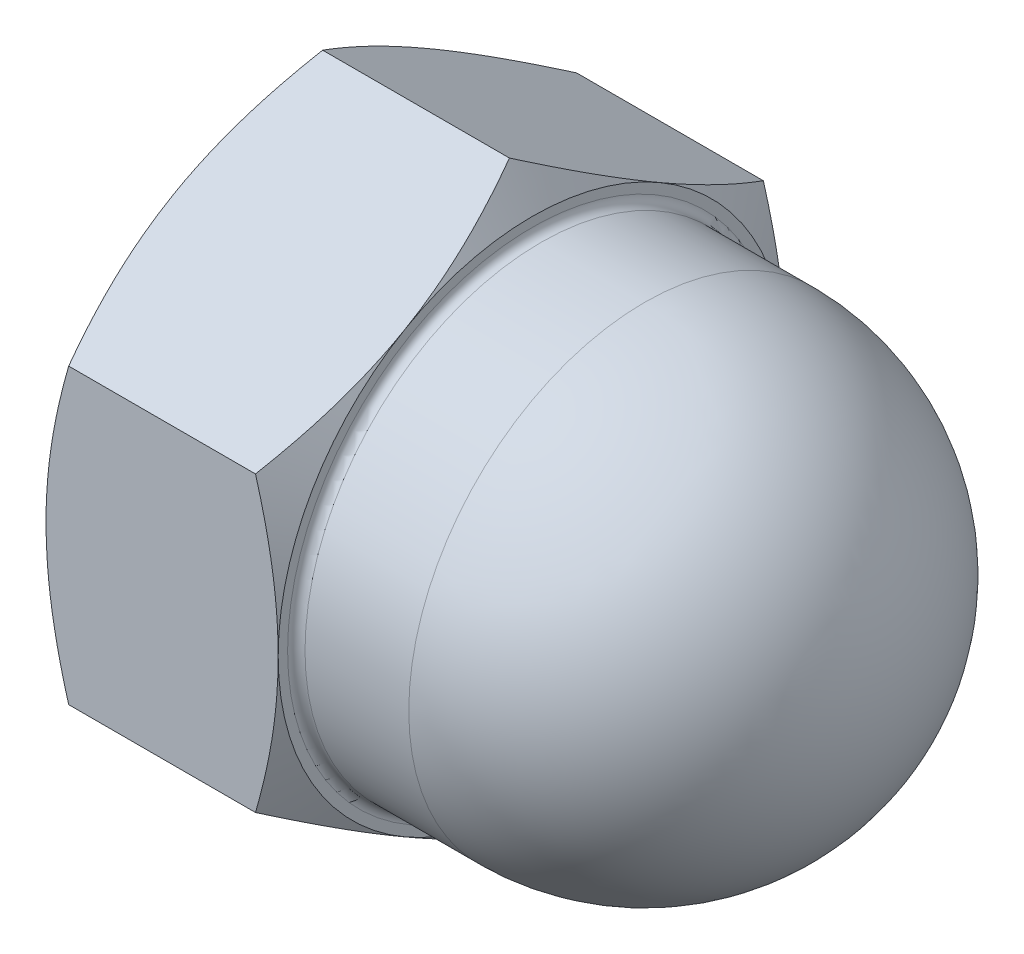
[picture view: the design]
ISO-10303-21;
HEADER;
FILE_DESCRIPTION(('STEP AP214'),'2;1');
FILE_NAME('part.step','',(''),(''),'','','');
FILE_SCHEMA(('AUTOMOTIVE_DESIGN { 1 0 10303 214 1 1 1 1 }'));
ENDSEC;
DATA;
#1=APPLICATION_CONTEXT('core data for automotive mechanical design processes');
#2=APPLICATION_PROTOCOL_DEFINITION('international standard','automotive_design',2000,#1);
#3=PRODUCT_CONTEXT('',#1,'mechanical');
#4=PRODUCT('Part','Part','',(#3));
#5=PRODUCT_RELATED_PRODUCT_CATEGORY('part','',(#4));
#6=PRODUCT_DEFINITION_FORMATION('','',#4);
#7=PRODUCT_DEFINITION_CONTEXT('part definition',#1,'design');
#8=PRODUCT_DEFINITION('design','',#6,#7);
#9=PRODUCT_DEFINITION_SHAPE('','',#8);
#10=(LENGTH_UNIT() NAMED_UNIT(*) SI_UNIT(.MILLI.,.METRE.));
#11=(NAMED_UNIT(*) PLANE_ANGLE_UNIT() SI_UNIT($,.RADIAN.));
#12=(NAMED_UNIT(*) SI_UNIT($,.STERADIAN.) SOLID_ANGLE_UNIT());
#13=UNCERTAINTY_MEASURE_WITH_UNIT(LENGTH_MEASURE(1.E-05),#10,'distance_accuracy_value','');
#14=(GEOMETRIC_REPRESENTATION_CONTEXT(3) GLOBAL_UNCERTAINTY_ASSIGNED_CONTEXT((#13)) GLOBAL_UNIT_ASSIGNED_CONTEXT((#10,
#11,#12)) REPRESENTATION_CONTEXT('',''));
#15=CARTESIAN_POINT('',(0.,0.,0.));
#16=DIRECTION('',(0.,0.,1.));
#17=DIRECTION('',(1.,0.,0.));
#18=AXIS2_PLACEMENT_3D('',#15,#16,#17);
#19=CARTESIAN_POINT('',(0.,4.04145188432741,0.));
#20=DIRECTION('',(-1.,0.,0.));
#21=DIRECTION('',(0.,0.,1.));
#22=AXIS2_PLACEMENT_3D('',#19,#20,#21);
#23=PLANE('',#22);
#24=CARTESIAN_POINT('',(0.,0.,0.));
#25=DIRECTION('',(-1.,0.,0.));
#26=DIRECTION('',(0.,0.,1.));
#27=AXIS2_PLACEMENT_3D('',#24,#25,#26);
#28=CIRCLE('',#27,2.);
#29=CARTESIAN_POINT('',(0.,0.,2.));
#30=VERTEX_POINT('',#29);
#31=EDGE_CURVE('E301',#30,#30,#28,.T.);
#32=ORIENTED_EDGE('',*,*,#31,.F.);
#33=EDGE_LOOP('',(#32));
#34=FACE_BOUND('',#33,.T.);
#35=CARTESIAN_POINT('',(0.,0.,0.));
#36=DIRECTION('',(-1.,0.,0.));
#37=DIRECTION('',(0.,0.,1.));
#38=AXIS2_PLACEMENT_3D('',#35,#36,#37);
#39=CIRCLE('',#38,3.5);
#40=CARTESIAN_POINT('',(0.,-3.03108891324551,1.75000000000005));
#41=VERTEX_POINT('',#40);
#42=CARTESIAN_POINT('',(0.,0.,3.5));
#43=VERTEX_POINT('',#42);
#44=EDGE_CURVE('E183',#41,#43,#39,.T.);
#45=ORIENTED_EDGE('',*,*,#44,.T.);
#46=CARTESIAN_POINT('',(0.,0.,0.));
#47=DIRECTION('',(-1.,0.,0.));
#48=DIRECTION('',(0.,0.,1.));
#49=AXIS2_PLACEMENT_3D('',#46,#47,#48);
#50=CIRCLE('',#49,3.5);
#51=CARTESIAN_POINT('',(0.,3.03108891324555,1.74999999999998));
#52=VERTEX_POINT('',#51);
#53=EDGE_CURVE('E293',#43,#52,#50,.T.);
#54=ORIENTED_EDGE('',*,*,#53,.T.);
#55=CARTESIAN_POINT('',(0.,3.03108891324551,-1.75000000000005));
#56=VERTEX_POINT('',#55);
#57=EDGE_CURVE('E182',#52,#56,#39,.T.);
#58=ORIENTED_EDGE('',*,*,#57,.T.);
#59=CARTESIAN_POINT('',(0.,0.,-3.5));
#60=VERTEX_POINT('',#59);
#61=EDGE_CURVE('E349',#56,#60,#39,.T.);
#62=ORIENTED_EDGE('',*,*,#61,.T.);
#63=CARTESIAN_POINT('',(0.,-3.03108891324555,-1.74999999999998));
#64=VERTEX_POINT('',#63);
#65=EDGE_CURVE('E348',#60,#64,#39,.T.);
#66=ORIENTED_EDGE('',*,*,#65,.T.);
#67=EDGE_CURVE('E346',#64,#41,#39,.T.);
#68=ORIENTED_EDGE('',*,*,#67,.T.);
#69=EDGE_LOOP('',(#45,#54,#58,#62,#66,#68));
#70=FACE_BOUND('',#69,.T.);
#71=ADVANCED_FACE('F32',(#34,#70),#23,.T.);
#72=CARTESIAN_POINT('',(3.2,4.04145188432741,0.));
#73=DIRECTION('',(-1.,0.,0.));
#74=DIRECTION('',(0.,0.,1.));
#75=AXIS2_PLACEMENT_3D('',#72,#73,#74);
#76=PLANE('',#75);
#77=CARTESIAN_POINT('',(3.2,0.,0.));
#78=DIRECTION('',(-1.,0.,0.));
#79=DIRECTION('',(0.,0.,1.));
#80=AXIS2_PLACEMENT_3D('',#77,#78,#79);
#81=CIRCLE('',#80,3.37);
#82=CARTESIAN_POINT('',(3.2,0.,3.37));
#83=VERTEX_POINT('',#82);
#84=EDGE_CURVE('E11',#83,#83,#81,.T.);
#85=ORIENTED_EDGE('',*,*,#84,.T.);
#86=EDGE_LOOP('',(#85));
#87=FACE_BOUND('',#86,.T.);
#88=CARTESIAN_POINT('',(3.2,0.,0.));
#89=DIRECTION('',(-1.,0.,0.));
#90=DIRECTION('',(0.,0.,1.));
#91=AXIS2_PLACEMENT_3D('',#88,#89,#90);
#92=CIRCLE('',#91,3.5);
#93=CARTESIAN_POINT('',(3.2,0.,3.5));
#94=VERTEX_POINT('',#93);
#95=CARTESIAN_POINT('',(3.2,3.03108891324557,1.74999999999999));
#96=VERTEX_POINT('',#95);
#97=EDGE_CURVE('E294',#94,#96,#92,.T.);
#98=ORIENTED_EDGE('',*,*,#97,.F.);
#99=CARTESIAN_POINT('',(3.2,-3.03108891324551,1.75000000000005));
#100=VERTEX_POINT('',#99);
#101=EDGE_CURVE('E47',#100,#94,#92,.T.);
#102=ORIENTED_EDGE('',*,*,#101,.F.);
#103=CARTESIAN_POINT('',(3.2,-3.03108891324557,-1.74999999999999));
#104=VERTEX_POINT('',#103);
#105=EDGE_CURVE('E283',#104,#100,#92,.T.);
#106=ORIENTED_EDGE('',*,*,#105,.F.);
#107=CARTESIAN_POINT('',(3.2,0.,-3.5));
#108=VERTEX_POINT('',#107);
#109=EDGE_CURVE('E55',#108,#104,#92,.T.);
#110=ORIENTED_EDGE('',*,*,#109,.F.);
#111=CARTESIAN_POINT('',(3.2,3.03108891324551,-1.75000000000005));
#112=VERTEX_POINT('',#111);
#113=EDGE_CURVE('E292',#112,#108,#92,.T.);
#114=ORIENTED_EDGE('',*,*,#113,.F.);
#115=EDGE_CURVE('E296',#96,#112,#92,.T.);
#116=ORIENTED_EDGE('',*,*,#115,.F.);
#117=EDGE_LOOP('',(#98,#102,#106,#110,#114,#116));
#118=FACE_BOUND('',#117,.T.);
#119=ADVANCED_FACE('F142',(#87,#118),#76,.F.);
#120=CARTESIAN_POINT('',(0.,0.,0.));
#121=DIRECTION('',(-1.,0.,0.));
#122=DIRECTION('',(0.,0.,1.));
#123=AXIS2_PLACEMENT_3D('',#120,#121,#122);
#124=CYLINDRICAL_SURFACE('',#123,3.25);
#125=CARTESIAN_POINT('',(3.32,0.,0.));
#126=DIRECTION('',(-1.,0.,0.));
#127=DIRECTION('',(0.,0.,1.));
#128=AXIS2_PLACEMENT_3D('',#125,#126,#127);
#129=CIRCLE('',#128,3.25);
#130=CARTESIAN_POINT('',(3.32,0.,3.25));
#131=VERTEX_POINT('',#130);
#132=EDGE_CURVE('E40',#131,#131,#129,.F.);
#133=ORIENTED_EDGE('',*,*,#132,.T.);
#134=EDGE_LOOP('',(#133));
#135=FACE_BOUND('',#134,.T.);
#136=CARTESIAN_POINT('',(4.75,0.,0.));
#137=DIRECTION('',(-1.,0.,0.));
#138=DIRECTION('',(0.,0.,1.));
#139=AXIS2_PLACEMENT_3D('',#136,#137,#138);
#140=CIRCLE('',#139,3.25);
#141=CARTESIAN_POINT('',(4.75,0.,3.25));
#142=VERTEX_POINT('',#141);
#143=EDGE_CURVE('E331',#142,#142,#140,.T.);
#144=ORIENTED_EDGE('',*,*,#143,.T.);
#145=EDGE_LOOP('',(#144));
#146=FACE_BOUND('',#145,.T.);
#147=ADVANCED_FACE('F148',(#135,#146),#124,.T.);
#148=CARTESIAN_POINT('',(4.75,0.,0.));
#149=DIRECTION('',(-1.,0.,0.));
#150=DIRECTION('',(0.,1.,0.));
#151=AXIS2_PLACEMENT_3D('',#148,#149,#150);
#152=SPHERICAL_SURFACE('',#151,3.25);
#153=ORIENTED_EDGE('',*,*,#143,.F.);
#154=EDGE_LOOP('',(#153));
#155=FACE_BOUND('',#154,.T.);
#156=ADVANCED_FACE('F465',(#155),#152,.T.);
#157=CARTESIAN_POINT('',(2.55060495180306,0.,0.));
#158=DIRECTION('',(-1.,0.,0.));
#159=DIRECTION('',(0.,0.,1.));
#160=AXIS2_PLACEMENT_3D('',#157,#158,#159);
#161=CONICAL_SURFACE('',#160,4.62478521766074,1.0471975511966);
#162=CARTESIAN_POINT('',(2.88732593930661,4.04156735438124,-0.00020000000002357));
#163=CARTESIAN_POINT('',(2.93861421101,3.95276673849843,0.153607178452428));
#164=CARTESIAN_POINT('',(2.98525904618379,3.86319960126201,0.308742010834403));
#165=CARTESIAN_POINT('',(3.06667812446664,3.68251437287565,0.621698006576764));
#166=CARTESIAN_POINT('',(3.10142356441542,3.59139307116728,0.77952473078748));
#167=CARTESIAN_POINT('',(3.15550997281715,3.41027974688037,1.09322221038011));
#168=CARTESIAN_POINT('',(3.1752109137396,3.32031559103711,1.24904469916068));
#169=CARTESIAN_POINT('',(3.19872986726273,3.13996396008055,1.56142288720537));
#170=CARTESIAN_POINT('',(3.20256735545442,3.04957714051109,1.71797745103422));
#171=CARTESIAN_POINT('',(3.19458469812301,2.88068384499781,2.01050921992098));
#172=CARTESIAN_POINT('',(3.18472456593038,2.80215208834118,2.1465302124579));
#173=CARTESIAN_POINT('',(3.15347353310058,2.64560020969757,2.41768602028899));
#174=CARTESIAN_POINT('',(3.13207195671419,2.56758062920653,2.55281989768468));
#175=CARTESIAN_POINT('',(3.07856959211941,2.41070596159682,2.82453479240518));
#176=CARTESIAN_POINT('',(3.0462420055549,2.33187072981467,2.96108141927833));
#177=CARTESIAN_POINT('',(2.97287106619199,2.17537608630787,3.2321380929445));
#178=CARTESIAN_POINT('',(2.93184495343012,2.09771466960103,3.36665161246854));
#179=CARTESIAN_POINT('',(2.88732593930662,2.0206104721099,3.5002));
#180=B_SPLINE_CURVE_WITH_KNOTS('',3,(#162,#163,#164,#165,#166,#167,#168,#169,#170,#171,#172,
#173,#174,#175,#176,#177,#178,#179),.UNSPECIFIED.,.F.,.F.,(4,2,2,2,2,2,2,2,4),(0.,
0.554793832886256,1.11092123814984,1.6532846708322,2.19498204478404,2.66665130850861,
3.13875761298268,3.62133612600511,4.10296698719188),.UNSPECIFIED.);
#181=CARTESIAN_POINT('',(2.88739260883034,4.04145188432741,0.));
#182=VERTEX_POINT('',#181);
#183=EDGE_CURVE('E209',#182,#96,#180,.T.);
#184=ORIENTED_EDGE('',*,*,#183,.T.);
#185=ORIENTED_EDGE('',*,*,#115,.T.);
#186=CARTESIAN_POINT('',(2.88732593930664,2.02061047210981,-3.5002));
#187=CARTESIAN_POINT('',(2.93861421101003,2.10941108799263,-3.34639282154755));
#188=CARTESIAN_POINT('',(2.98525904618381,2.19897822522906,-3.19125798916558));
#189=CARTESIAN_POINT('',(3.06667812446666,2.37966345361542,-2.87830199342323));
#190=CARTESIAN_POINT('',(3.10142356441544,2.47078475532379,-2.72047526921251));
#191=CARTESIAN_POINT('',(3.15550997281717,2.65189807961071,-2.40677778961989));
#192=CARTESIAN_POINT('',(3.17521091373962,2.74186223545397,-2.25095530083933));
#193=CARTESIAN_POINT('',(3.19872986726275,2.92221386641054,-1.93857711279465));
#194=CARTESIAN_POINT('',(3.20256735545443,3.01260068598,-1.78202254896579));
#195=CARTESIAN_POINT('',(3.19458469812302,3.18149398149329,-1.48949078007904));
#196=CARTESIAN_POINT('',(3.18472456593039,3.26002573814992,-1.35346978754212));
#197=CARTESIAN_POINT('',(3.15347353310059,3.41657761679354,-1.08231397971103));
#198=CARTESIAN_POINT('',(3.13207195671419,3.49459719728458,-0.947180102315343));
#199=CARTESIAN_POINT('',(3.07856959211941,3.6514718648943,-0.675465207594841));
#200=CARTESIAN_POINT('',(3.0462420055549,3.73030709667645,-0.538918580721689));
#201=CARTESIAN_POINT('',(2.97287106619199,3.88680174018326,-0.267861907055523));
#202=CARTESIAN_POINT('',(2.93184495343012,3.96446315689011,-0.133348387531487));
#203=CARTESIAN_POINT('',(2.88732593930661,4.04156735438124,0.000199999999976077));
#204=B_SPLINE_CURVE_WITH_KNOTS('',3,(#186,#187,#188,#189,#190,#191,#192,#193,#194,#195,#196,
#197,#198,#199,#200,#201,#202,#203),.UNSPECIFIED.,.F.,.F.,(4,2,2,2,2,2,2,2,4),(0.,
0.554793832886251,1.11092123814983,1.65328467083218,2.19498204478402,2.66665130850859,
3.13875761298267,3.6213361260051,4.10296698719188),.UNSPECIFIED.);
#205=EDGE_CURVE('E174',#112,#182,#204,.T.);
#206=ORIENTED_EDGE('',*,*,#205,.T.);
#207=EDGE_LOOP('',(#184,#185,#206));
#208=FACE_BOUND('',#207,.T.);
#209=ADVANCED_FACE('F192',(#208),#161,.T.);
#210=CARTESIAN_POINT('',(2.88739260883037,2.02072594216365,-3.5));
#211=VERTEX_POINT('',#210);
#212=EDGE_CURVE('E181',#211,#112,#204,.T.);
#213=ORIENTED_EDGE('',*,*,#212,.T.);
#214=ORIENTED_EDGE('',*,*,#113,.T.);
#215=CARTESIAN_POINT('',(1.50247795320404,-5.40611730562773,-3.5));
#216=CARTESIAN_POINT('',(1.57645553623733,-5.25343314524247,-3.5));
#217=CARTESIAN_POINT('',(1.64971746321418,-5.10039613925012,-3.5));
#218=CARTESIAN_POINT('',(1.79440706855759,-4.79342871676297,-3.5));
#219=CARTESIAN_POINT('',(1.86583445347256,-4.63949816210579,-3.5));
#220=CARTESIAN_POINT('',(2.00681607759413,-4.32975228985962,-3.5));
#221=CARTESIAN_POINT('',(2.07635780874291,-4.17393125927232,-3.5));
#222=CARTESIAN_POINT('',(2.21256617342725,-3.86104221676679,-3.5));
#223=CARTESIAN_POINT('',(2.27923294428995,-3.70397426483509,-3.5));
#224=CARTESIAN_POINT('',(2.41098213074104,-3.38335155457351,-3.5));
#225=CARTESIAN_POINT('',(2.47594796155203,-3.21974862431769,-3.5));
#226=CARTESIAN_POINT('',(2.60090973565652,-2.8906206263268,-3.5));
#227=CARTESIAN_POINT('',(2.66090511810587,-2.72509534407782,-3.5));
#228=CARTESIAN_POINT('',(2.77433498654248,-2.39217631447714,-3.5));
#229=CARTESIAN_POINT('',(2.82778294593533,-2.22478720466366,-3.5));
#230=CARTESIAN_POINT('',(2.9263884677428,-1.88760803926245,-3.5));
#231=CARTESIAN_POINT('',(2.97154866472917,-1.71781876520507,-3.5));
#232=CARTESIAN_POINT('',(3.05115731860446,-1.3766839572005,-3.5));
#233=CARTESIAN_POINT('',(3.08566319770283,-1.20535207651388,-3.5));
#234=CARTESIAN_POINT('',(3.14199871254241,-0.860580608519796,-3.5));
#235=CARTESIAN_POINT('',(3.16382950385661,-0.687141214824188,-3.5));
#236=CARTESIAN_POINT('',(3.19278708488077,-0.341277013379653,-3.5));
#237=CARTESIAN_POINT('',(3.20010114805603,-0.168868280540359,-3.5));
#238=CARTESIAN_POINT('',(3.19989678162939,0.175953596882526,-3.5));
#239=CARTESIAN_POINT('',(3.19237803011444,0.348366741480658,-3.5));
#240=CARTESIAN_POINT('',(3.16749411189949,0.641728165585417,-3.5));
#241=CARTESIAN_POINT('',(3.15364835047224,0.762992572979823,-3.5));
#242=CARTESIAN_POINT('',(3.1194932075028,1.0046139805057,-3.5));
#243=CARTESIAN_POINT('',(3.09918292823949,1.12497085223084,-3.5));
#244=CARTESIAN_POINT('',(3.0296249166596,1.48453137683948,-3.5));
#245=CARTESIAN_POINT('',(2.97176332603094,1.72208616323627,-3.5));
#246=CARTESIAN_POINT('',(2.87168347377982,2.07725702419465,-3.5));
#247=CARTESIAN_POINT('',(2.83565084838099,2.19672070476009,-3.5));
#248=CARTESIAN_POINT('',(2.75990634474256,2.43448713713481,-3.5));
#249=CARTESIAN_POINT('',(2.72019444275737,2.5527898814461,-3.5));
#250=CARTESIAN_POINT('',(2.63772343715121,2.78827311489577,-3.5));
#251=CARTESIAN_POINT('',(2.59496538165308,2.90545397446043,-3.5));
#252=CARTESIAN_POINT('',(2.50689851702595,3.13884909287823,-3.5));
#253=CARTESIAN_POINT('',(2.46158973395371,3.25506336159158,-3.5));
#254=CARTESIAN_POINT('',(2.35422054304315,3.52315412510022,-3.5));
#255=CARTESIAN_POINT('',(2.29138349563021,3.67471898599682,-3.5));
#256=CARTESIAN_POINT('',(2.1627830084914,3.97660499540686,-3.5));
#257=CARTESIAN_POINT('',(2.09701941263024,4.12692607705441,-3.5));
#258=CARTESIAN_POINT('',(1.89621995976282,4.57638177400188,-3.5));
#259=CARTESIAN_POINT('',(1.75769684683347,4.87395662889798,-3.5));
#260=CARTESIAN_POINT('',(1.47441483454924,5.46643785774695,-3.5));
#261=CARTESIAN_POINT('',(1.32965015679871,5.76134143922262,-3.5));
#262=CARTESIAN_POINT('',(1.03588470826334,6.34903869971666,-3.5));
#263=CARTESIAN_POINT('',(0.88688378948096,6.64183230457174,-3.5));
#264=CARTESIAN_POINT('',(0.59798130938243,7.2023528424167,-3.5));
#265=CARTESIAN_POINT('',(0.45831279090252,7.4702002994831,-3.5));
#266=CARTESIAN_POINT('',(0.177045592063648,8.00488966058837,-3.5));
#267=CARTESIAN_POINT('',(0.035446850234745,8.27173153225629,-3.5));
#268=CARTESIAN_POINT('',(-0.248895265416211,8.80400274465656,-3.5));
#269=CARTESIAN_POINT('',(-0.3916351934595,9.06943392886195,-3.5));
#270=CARTESIAN_POINT('',(-0.678279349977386,9.59964936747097,-3.5));
#271=CARTESIAN_POINT('',(-0.822183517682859,9.86443365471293,-3.5));
#272=CARTESIAN_POINT('',(-0.966524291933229,10.128978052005,-3.5));
#273=B_SPLINE_CURVE_WITH_KNOTS('',3,(#215,#216,#217,#218,#219,#220,#221,#222,#223,#224,#225,
#226,#227,#228,#229,#230,#231,#232,#233,#234,#235,#236,#237,#238,#239,#240,#241,#242,#243,#244,
#245,#246,#247,#248,#249,#250,#251,#252,#253,#254,#255,#256,#257,#258,#259,#260,#261,#262,#263,
#264,#265,#266,#267,#268,#269,#270,#271,#272),.UNSPECIFIED.,.F.,.F.,(4,2,2,2,2,2,2,2,2,2,2,2,2,
2,2,2,2,2,2,2,2,2,2,2,2,2,2,2,4),(0.,0.508991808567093,1.01806453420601,1.5299457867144,
2.04180256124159,2.56982945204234,3.09791584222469,3.62489659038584,4.1517095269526,
4.67563150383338,5.19950570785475,5.71657655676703,6.23365862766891,6.5996375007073,
6.96566721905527,7.69814300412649,8.07245060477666,8.44676062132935,8.82094246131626,
9.19512047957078,9.68730266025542,10.1795111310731,11.1640972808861,12.1496153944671,
13.1351679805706,14.041385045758,14.9476310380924,15.851760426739,16.7558429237),.UNSPECIFIED.);
#274=EDGE_CURVE('E202',#211,#108,#273,.F.);
#275=ORIENTED_EDGE('',*,*,#274,.F.);
#276=EDGE_LOOP('',(#213,#214,#275));
#277=FACE_BOUND('',#276,.T.);
#278=ADVANCED_FACE('F187',(#277),#161,.T.);
#279=CARTESIAN_POINT('',(2.88732593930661,-4.04156735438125,0.000200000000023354));
#280=CARTESIAN_POINT('',(2.93861421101,-3.95276673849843,-0.153607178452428));
#281=CARTESIAN_POINT('',(2.98525904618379,-3.86319960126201,-0.308742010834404));
#282=CARTESIAN_POINT('',(3.06667812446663,-3.68251437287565,-0.621698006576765));
#283=CARTESIAN_POINT('',(3.10142356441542,-3.59139307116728,-0.779524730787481));
#284=CARTESIAN_POINT('',(3.15550997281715,-3.41027974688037,-1.09322221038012));
#285=CARTESIAN_POINT('',(3.1752109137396,-3.32031559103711,-1.24904469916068));
#286=CARTESIAN_POINT('',(3.19872986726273,-3.13996396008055,-1.56142288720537));
#287=CARTESIAN_POINT('',(3.20256735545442,-3.04957714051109,-1.71797745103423));
#288=CARTESIAN_POINT('',(3.194584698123,-2.88068384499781,-2.01050921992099));
#289=CARTESIAN_POINT('',(3.18472456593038,-2.80215208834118,-2.1465302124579));
#290=CARTESIAN_POINT('',(3.15347353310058,-2.64560020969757,-2.41768602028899));
#291=CARTESIAN_POINT('',(3.13207195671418,-2.56758062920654,-2.55281989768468));
#292=CARTESIAN_POINT('',(3.07856959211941,-2.41070596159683,-2.82453479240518));
#293=CARTESIAN_POINT('',(3.0462420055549,-2.33187072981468,-2.96108141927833));
#294=CARTESIAN_POINT('',(2.97287106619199,-2.17537608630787,-3.2321380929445));
#295=CARTESIAN_POINT('',(2.93184495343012,-2.09771466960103,-3.36665161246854));
#296=CARTESIAN_POINT('',(2.88732593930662,-2.0206104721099,-3.5002));
#297=B_SPLINE_CURVE_WITH_KNOTS('',3,(#279,#280,#281,#282,#283,#284,#285,#286,#287,#288,#289,
#290,#291,#292,#293,#294,#295,#296),.UNSPECIFIED.,.F.,.F.,(4,2,2,2,2,2,2,2,4),(0.,
0.554793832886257,1.11092123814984,1.6532846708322,2.19498204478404,2.66665130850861,
3.13875761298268,3.62133612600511,4.10296698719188),.UNSPECIFIED.);
#298=CARTESIAN_POINT('',(2.88739260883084,-2.02072594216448,-3.5));
#299=VERTEX_POINT('',#298);
#300=EDGE_CURVE('E214',#104,#299,#297,.T.);
#301=ORIENTED_EDGE('',*,*,#300,.T.);
#302=EDGE_CURVE('E269',#108,#299,#273,.F.);
#303=ORIENTED_EDGE('',*,*,#302,.F.);
#304=ORIENTED_EDGE('',*,*,#109,.T.);
#305=EDGE_LOOP('',(#301,#303,#304));
#306=FACE_BOUND('',#305,.T.);
#307=ADVANCED_FACE('F191',(#306),#161,.T.);
#308=CARTESIAN_POINT('',(2.88732593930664,-2.02061047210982,3.5002));
#309=CARTESIAN_POINT('',(2.93861421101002,-2.10941108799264,3.34639282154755));
#310=CARTESIAN_POINT('',(2.98525904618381,-2.19897822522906,3.19125798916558));
#311=CARTESIAN_POINT('',(3.06667812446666,-2.37966345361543,2.87830199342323));
#312=CARTESIAN_POINT('',(3.10142356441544,-2.4707847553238,2.72047526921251));
#313=CARTESIAN_POINT('',(3.15550997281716,-2.65189807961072,2.40677778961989));
#314=CARTESIAN_POINT('',(3.17521091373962,-2.74186223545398,2.25095530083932));
#315=CARTESIAN_POINT('',(3.19872986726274,-2.92221386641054,1.93857711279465));
#316=CARTESIAN_POINT('',(3.20256735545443,-3.01260068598,1.78202254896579));
#317=CARTESIAN_POINT('',(3.19458469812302,-3.18149398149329,1.48949078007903));
#318=CARTESIAN_POINT('',(3.18472456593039,-3.26002573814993,1.35346978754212));
#319=CARTESIAN_POINT('',(3.15347353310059,-3.41657761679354,1.08231397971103));
#320=CARTESIAN_POINT('',(3.13207195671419,-3.49459719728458,0.947180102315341));
#321=CARTESIAN_POINT('',(3.07856959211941,-3.6514718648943,0.67546520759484));
#322=CARTESIAN_POINT('',(3.0462420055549,-3.73030709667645,0.538918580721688));
#323=CARTESIAN_POINT('',(2.97287106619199,-3.88680174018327,0.267861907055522));
#324=CARTESIAN_POINT('',(2.93184495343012,-3.96446315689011,0.133348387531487));
#325=CARTESIAN_POINT('',(2.88732593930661,-4.04156735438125,-0.000199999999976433));
#326=B_SPLINE_CURVE_WITH_KNOTS('',3,(#308,#309,#310,#311,#312,#313,#314,#315,#316,#317,#318,
#319,#320,#321,#322,#323,#324,#325),.UNSPECIFIED.,.F.,.F.,(4,2,2,2,2,2,2,2,4),(0.,
0.554793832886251,1.11092123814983,1.65328467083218,2.19498204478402,2.66665130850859,
3.13875761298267,3.6213361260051,4.10296698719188),.UNSPECIFIED.);
#327=CARTESIAN_POINT('',(2.88739260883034,-4.04145188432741,0.));
#328=VERTEX_POINT('',#327);
#329=EDGE_CURVE('E219',#100,#328,#326,.T.);
#330=ORIENTED_EDGE('',*,*,#329,.T.);
#331=EDGE_CURVE('E225',#328,#104,#297,.T.);
#332=ORIENTED_EDGE('',*,*,#331,.T.);
#333=ORIENTED_EDGE('',*,*,#105,.T.);
#334=EDGE_LOOP('',(#330,#332,#333));
#335=FACE_BOUND('',#334,.T.);
#336=ADVANCED_FACE('F281',(#335),#161,.T.);
#337=CARTESIAN_POINT('',(1.50247795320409,-5.40611730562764,3.5));
#338=CARTESIAN_POINT('',(1.57645553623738,-5.25343314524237,3.5));
#339=CARTESIAN_POINT('',(1.64971746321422,-5.10039613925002,3.5));
#340=CARTESIAN_POINT('',(1.79440706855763,-4.79342871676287,3.5));
#341=CARTESIAN_POINT('',(1.86583445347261,-4.6394981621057,3.5));
#342=CARTESIAN_POINT('',(2.00681607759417,-4.32975228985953,3.5));
#343=CARTESIAN_POINT('',(2.07635780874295,-4.17393125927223,3.5));
#344=CARTESIAN_POINT('',(2.21256617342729,-3.8610422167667,3.5));
#345=CARTESIAN_POINT('',(2.27923294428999,-3.703974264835,3.5));
#346=CARTESIAN_POINT('',(2.41098213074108,-3.38335155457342,3.5));
#347=CARTESIAN_POINT('',(2.47594796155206,-3.2197486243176,3.5));
#348=CARTESIAN_POINT('',(2.60090973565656,-2.89062062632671,3.5));
#349=CARTESIAN_POINT('',(2.6609051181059,-2.72509534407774,3.5));
#350=CARTESIAN_POINT('',(2.77433498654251,-2.39217631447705,3.5));
#351=CARTESIAN_POINT('',(2.82778294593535,-2.22478720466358,3.5));
#352=CARTESIAN_POINT('',(2.92638846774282,-1.88760803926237,3.5));
#353=CARTESIAN_POINT('',(2.97154866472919,-1.71781876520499,3.5));
#354=CARTESIAN_POINT('',(3.05115731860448,-1.37668395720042,3.5));
#355=CARTESIAN_POINT('',(3.08566319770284,-1.20535207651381,3.5));
#356=CARTESIAN_POINT('',(3.14199871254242,-0.860580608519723,3.5));
#357=CARTESIAN_POINT('',(3.16382950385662,-0.687141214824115,3.5));
#358=CARTESIAN_POINT('',(3.19278708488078,-0.341277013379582,3.5));
#359=CARTESIAN_POINT('',(3.20010114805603,-0.16886828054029,3.5));
#360=CARTESIAN_POINT('',(3.19989678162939,0.175953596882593,3.5));
#361=CARTESIAN_POINT('',(3.19237803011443,0.348366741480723,3.5));
#362=CARTESIAN_POINT('',(3.16749411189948,0.641728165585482,3.5));
#363=CARTESIAN_POINT('',(3.15364835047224,0.762992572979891,3.5));
#364=CARTESIAN_POINT('',(3.11949320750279,1.00461398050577,3.5));
#365=CARTESIAN_POINT('',(3.09918292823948,1.12497085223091,3.5));
#366=CARTESIAN_POINT('',(3.02962491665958,1.48453137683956,3.5));
#367=CARTESIAN_POINT('',(2.97176332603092,1.72208616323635,3.5));
#368=CARTESIAN_POINT('',(2.87168347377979,2.07725702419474,3.5));
#369=CARTESIAN_POINT('',(2.83565084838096,2.19672070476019,3.5));
#370=CARTESIAN_POINT('',(2.75990634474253,2.43448713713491,3.5));
#371=CARTESIAN_POINT('',(2.72019444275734,2.55278988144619,3.5));
#372=CARTESIAN_POINT('',(2.63772343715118,2.78827311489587,3.5));
#373=CARTESIAN_POINT('',(2.59496538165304,2.90545397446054,3.5));
#374=CARTESIAN_POINT('',(2.50689851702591,3.13884909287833,3.5));
#375=CARTESIAN_POINT('',(2.46158973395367,3.25506336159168,3.5));
#376=CARTESIAN_POINT('',(2.3542205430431,3.52315412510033,3.5));
#377=CARTESIAN_POINT('',(2.29138349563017,3.67471898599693,3.5));
#378=CARTESIAN_POINT('',(2.16278300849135,3.97660499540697,3.5));
#379=CARTESIAN_POINT('',(2.0970194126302,4.12692607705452,3.5));
#380=CARTESIAN_POINT('',(1.89621995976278,4.57638177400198,3.5));
#381=CARTESIAN_POINT('',(1.75769684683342,4.87395662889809,3.5));
#382=CARTESIAN_POINT('',(1.47441483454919,5.46643785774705,3.5));
#383=CARTESIAN_POINT('',(1.32965015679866,5.76134143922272,3.5));
#384=CARTESIAN_POINT('',(1.03588470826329,6.34903869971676,3.5));
#385=CARTESIAN_POINT('',(0.886883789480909,6.64183230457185,3.5));
#386=CARTESIAN_POINT('',(0.597981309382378,7.2023528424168,3.5));
#387=CARTESIAN_POINT('',(0.458312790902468,7.47020029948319,3.5));
#388=CARTESIAN_POINT('',(0.177045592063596,8.00488966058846,3.5));
#389=CARTESIAN_POINT('',(0.0354468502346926,8.27173153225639,3.5));
#390=CARTESIAN_POINT('',(-0.248895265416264,8.80400274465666,3.5));
#391=CARTESIAN_POINT('',(-0.391635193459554,9.06943392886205,3.5));
#392=CARTESIAN_POINT('',(-0.67827934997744,9.59964936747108,3.5));
#393=CARTESIAN_POINT('',(-0.822183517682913,9.86443365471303,3.5));
#394=CARTESIAN_POINT('',(-0.966524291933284,10.1289780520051,3.5));
#395=B_SPLINE_CURVE_WITH_KNOTS('',3,(#337,#338,#339,#340,#341,#342,#343,#344,#345,#346,#347,
#348,#349,#350,#351,#352,#353,#354,#355,#356,#357,#358,#359,#360,#361,#362,#363,#364,#365,#366,
#367,#368,#369,#370,#371,#372,#373,#374,#375,#376,#377,#378,#379,#380,#381,#382,#383,#384,#385,
#386,#387,#388,#389,#390,#391,#392,#393,#394),.UNSPECIFIED.,.F.,.F.,(4,2,2,2,2,2,2,2,2,2,2,2,2,
2,2,2,2,2,2,2,2,2,2,2,2,2,2,2,4),(0.,0.50899180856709,1.018064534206,1.52994578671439,
2.04180256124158,2.56982945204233,3.09791584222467,3.62489659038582,4.15170952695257,
4.67563150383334,5.19950570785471,5.71657655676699,6.23365862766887,6.59963750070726,
6.96566721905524,7.69814300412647,8.07245060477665,8.44676062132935,8.82094246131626,
9.19512047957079,9.68730266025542,10.1795111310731,11.1640972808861,12.1496153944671,
13.1351679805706,14.041385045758,14.9476310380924,15.851760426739,16.7558429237),.UNSPECIFIED.);
#396=CARTESIAN_POINT('',(2.88739260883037,-2.02072594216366,3.5));
#397=VERTEX_POINT('',#396);
#398=EDGE_CURVE('E226',#94,#397,#395,.F.);
#399=ORIENTED_EDGE('',*,*,#398,.T.);
#400=EDGE_CURVE('E224',#397,#100,#326,.T.);
#401=ORIENTED_EDGE('',*,*,#400,.T.);
#402=ORIENTED_EDGE('',*,*,#101,.T.);
#403=EDGE_LOOP('',(#399,#401,#402));
#404=FACE_BOUND('',#403,.T.);
#405=ADVANCED_FACE('F501',(#404),#161,.T.);
#406=CARTESIAN_POINT('',(2.88739260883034,2.02072594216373,3.5));
#407=VERTEX_POINT('',#406);
#408=EDGE_CURVE('E274',#96,#407,#180,.T.);
#409=ORIENTED_EDGE('',*,*,#408,.T.);
#410=EDGE_CURVE('E566',#407,#94,#395,.F.);
#411=ORIENTED_EDGE('',*,*,#410,.T.);
#412=ORIENTED_EDGE('',*,*,#97,.T.);
#413=EDGE_LOOP('',(#409,#411,#412));
#414=FACE_BOUND('',#413,.T.);
#415=ADVANCED_FACE('F160',(#414),#161,.T.);
#416=CARTESIAN_POINT('',(3.2,2.02072594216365,-3.5));
#417=DIRECTION('',(0.,-0.86602540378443,0.500000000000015));
#418=DIRECTION('',(0.,-0.500000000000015,-0.86602540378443));
#419=AXIS2_PLACEMENT_3D('',#416,#417,#418);
#420=PLANE('',#419);
#421=ORIENTED_EDGE('',*,*,#212,.F.);
#422=DIRECTION('',(-1.,0.,0.));
#423=VECTOR('',#422,1.);
#424=CARTESIAN_POINT('',(3.2,2.02072594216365,-3.5));
#425=LINE('',#424,#423);
#426=CARTESIAN_POINT('',(0.312607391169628,2.02072594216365,-3.5));
#427=VERTEX_POINT('',#426);
#428=EDGE_CURVE('E330',#211,#427,#425,.T.);
#429=ORIENTED_EDGE('',*,*,#428,.T.);
#430=CARTESIAN_POINT('',(0.312674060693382,4.04156735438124,0.000199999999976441));
#431=CARTESIAN_POINT('',(0.261385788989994,3.95276673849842,-0.153607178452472));
#432=CARTESIAN_POINT('',(0.214740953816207,3.863199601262,-0.308742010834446));
#433=CARTESIAN_POINT('',(0.133321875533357,3.68251437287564,-0.621698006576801));
#434=CARTESIAN_POINT('',(0.0985764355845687,3.59139307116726,-0.779524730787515));
#435=CARTESIAN_POINT('',(0.0444900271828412,3.41027974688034,-1.09322221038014));
#436=CARTESIAN_POINT('',(0.0247890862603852,3.32031559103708,-1.24904469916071));
#437=CARTESIAN_POINT('',(0.00127013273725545,3.13996396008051,-1.56142288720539));
#438=CARTESIAN_POINT('',(-0.00256735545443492,3.04957714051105,-1.71797745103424));
#439=CARTESIAN_POINT('',(0.00541530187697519,2.88068384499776,-2.010509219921));
#440=CARTESIAN_POINT('',(0.0152754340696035,2.80215208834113,-2.14653021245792));
#441=CARTESIAN_POINT('',(0.0465264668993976,2.64560020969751,-2.417686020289));
#442=CARTESIAN_POINT('',(0.0679280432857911,2.56758062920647,-2.55281989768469));
#443=CARTESIAN_POINT('',(0.121430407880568,2.41070596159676,-2.82453479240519));
#444=CARTESIAN_POINT('',(0.153757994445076,2.3318707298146,-2.96108141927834));
#445=CARTESIAN_POINT('',(0.227128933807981,2.17537608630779,-3.2321380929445));
#446=CARTESIAN_POINT('',(0.268155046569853,2.09771466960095,-3.36665161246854));
#447=CARTESIAN_POINT('',(0.312674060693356,2.02061047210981,-3.5002));
#448=B_SPLINE_CURVE_WITH_KNOTS('',3,(#430,#431,#432,#433,#434,#435,#436,#437,#438,#439,#440,
#441,#442,#443,#444,#445,#446,#447),.UNSPECIFIED.,.F.,.F.,(4,2,2,2,2,2,2,2,4),(0.,
0.554793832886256,1.11092123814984,1.65328467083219,2.19498204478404,2.66665130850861,
3.13875761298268,3.62133612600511,4.10296698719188),.UNSPECIFIED.);
#449=EDGE_CURVE('E166',#56,#427,#448,.T.);
#450=ORIENTED_EDGE('',*,*,#449,.F.);
#451=CARTESIAN_POINT('',(0.312607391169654,4.04145188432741,0.));
#452=VERTEX_POINT('',#451);
#453=EDGE_CURVE('E327',#452,#56,#448,.T.);
#454=ORIENTED_EDGE('',*,*,#453,.F.);
#455=DIRECTION('',(-1.,0.,0.));
#456=VECTOR('',#455,1.);
#457=CARTESIAN_POINT('',(3.2,4.04145188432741,0.));
#458=LINE('',#457,#456);
#459=EDGE_CURVE('E324',#182,#452,#458,.T.);
#460=ORIENTED_EDGE('',*,*,#459,.F.);
#461=ORIENTED_EDGE('',*,*,#205,.F.);
#462=EDGE_LOOP('',(#421,#429,#450,#454,#460,#461));
#463=FACE_BOUND('',#462,.T.);
#464=ADVANCED_FACE('F155',(#463),#420,.F.);
#465=CARTESIAN_POINT('',(3.2,2.02072594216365,-3.5));
#466=DIRECTION('',(0.,0.,-1.));
#467=DIRECTION('',(-1.,0.,0.));
#468=AXIS2_PLACEMENT_3D('',#465,#466,#467);
#469=PLANE('',#468);
#470=ORIENTED_EDGE('',*,*,#428,.F.);
#471=ORIENTED_EDGE('',*,*,#274,.T.);
#472=ORIENTED_EDGE('',*,*,#302,.T.);
#473=DIRECTION('',(-1.,0.,0.));
#474=VECTOR('',#473,1.);
#475=CARTESIAN_POINT('',(3.2,-2.02072594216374,-3.5));
#476=LINE('',#475,#474);
#477=CARTESIAN_POINT('',(0.312607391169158,-2.02072594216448,-3.5));
#478=VERTEX_POINT('',#477);
#479=EDGE_CURVE('E288',#299,#478,#476,.T.);
#480=ORIENTED_EDGE('',*,*,#479,.T.);
#481=CARTESIAN_POINT('',(1.69752204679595,-5.40611730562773,-3.5));
#482=CARTESIAN_POINT('',(1.62354446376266,-5.25343314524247,-3.5));
#483=CARTESIAN_POINT('',(1.55028253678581,-5.10039613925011,-3.5));
#484=CARTESIAN_POINT('',(1.4055929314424,-4.79342871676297,-3.5));
#485=CARTESIAN_POINT('',(1.33416554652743,-4.63949816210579,-3.5));
#486=CARTESIAN_POINT('',(1.19318392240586,-4.32975228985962,-3.5));
#487=CARTESIAN_POINT('',(1.12364219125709,-4.17393125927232,-3.5));
#488=CARTESIAN_POINT('',(0.987433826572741,-3.86104221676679,-3.5));
#489=CARTESIAN_POINT('',(0.920767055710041,-3.70397426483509,-3.5));
#490=CARTESIAN_POINT('',(0.789017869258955,-3.38335155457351,-3.5));
#491=CARTESIAN_POINT('',(0.724052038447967,-3.21974862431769,-3.5));
#492=CARTESIAN_POINT('',(0.59909026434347,-2.89062062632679,-3.5));
#493=CARTESIAN_POINT('',(0.539094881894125,-2.72509534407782,-3.5));
#494=CARTESIAN_POINT('',(0.425665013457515,-2.39217631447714,-3.5));
#495=CARTESIAN_POINT('',(0.37221705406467,-2.22478720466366,-3.5));
#496=CARTESIAN_POINT('',(0.273611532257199,-1.88760803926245,-3.5));
#497=CARTESIAN_POINT('',(0.228451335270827,-1.71781876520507,-3.5));
#498=CARTESIAN_POINT('',(0.148842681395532,-1.3766839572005,-3.5));
#499=CARTESIAN_POINT('',(0.114336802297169,-1.20535207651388,-3.5));
#500=CARTESIAN_POINT('',(0.0580012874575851,-0.860580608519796,-3.5));
#501=CARTESIAN_POINT('',(0.0361704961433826,-0.687141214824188,-3.5));
#502=CARTESIAN_POINT('',(0.00721291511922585,-0.341277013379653,-3.5));
#503=CARTESIAN_POINT('',(-0.000101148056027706,-0.168868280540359,-3.5));
#504=CARTESIAN_POINT('',(0.000103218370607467,0.175953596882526,-3.5));
#505=CARTESIAN_POINT('',(0.00762196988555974,0.348366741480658,-3.5));
#506=CARTESIAN_POINT('',(0.0325058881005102,0.641728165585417,-3.5));
#507=CARTESIAN_POINT('',(0.0463516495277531,0.762992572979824,-3.5));
#508=CARTESIAN_POINT('',(0.0805067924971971,1.00461398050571,-3.5));
#509=CARTESIAN_POINT('',(0.100817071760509,1.12497085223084,-3.5));
#510=CARTESIAN_POINT('',(0.170375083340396,1.48453137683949,-3.5));
#511=CARTESIAN_POINT('',(0.228236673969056,1.72208616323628,-3.5));
#512=CARTESIAN_POINT('',(0.328316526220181,2.07725702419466,-3.5));
#513=CARTESIAN_POINT('',(0.364349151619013,2.1967207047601,-3.5));
#514=CARTESIAN_POINT('',(0.440093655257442,2.43448713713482,-3.5));
#515=CARTESIAN_POINT('',(0.479805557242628,2.55278988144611,-3.5));
#516=CARTESIAN_POINT('',(0.562276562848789,2.78827311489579,-3.5));
#517=CARTESIAN_POINT('',(0.605034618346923,2.90545397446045,-3.5));
#518=CARTESIAN_POINT('',(0.693101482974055,3.13884909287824,-3.5));
#519=CARTESIAN_POINT('',(0.738410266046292,3.25506336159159,-3.5));
#520=CARTESIAN_POINT('',(0.845779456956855,3.52315412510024,-3.5));
#521=CARTESIAN_POINT('',(0.908616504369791,3.67471898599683,-3.5));
#522=CARTESIAN_POINT('',(1.0372169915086,3.97660499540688,-3.5));
#523=CARTESIAN_POINT('',(1.10298058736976,4.12692607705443,-3.5));
#524=CARTESIAN_POINT('',(1.30378004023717,4.57638177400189,-3.5));
#525=CARTESIAN_POINT('',(1.44230315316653,4.873956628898,-3.5));
#526=CARTESIAN_POINT('',(1.72558516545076,5.46643785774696,-3.5));
#527=CARTESIAN_POINT('',(1.87034984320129,5.76134143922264,-3.5));
#528=CARTESIAN_POINT('',(2.16411529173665,6.34903869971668,-3.5));
#529=CARTESIAN_POINT('',(2.31311621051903,6.64183230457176,-3.5));
#530=CARTESIAN_POINT('',(2.60201869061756,7.20235284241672,-3.5));
#531=CARTESIAN_POINT('',(2.74168720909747,7.47020029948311,-3.5));
#532=CARTESIAN_POINT('',(3.02295440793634,8.00488966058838,-3.5));
#533=CARTESIAN_POINT('',(3.16455314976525,8.27173153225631,-3.5));
#534=CARTESIAN_POINT('',(3.4488952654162,8.80400274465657,-3.5));
#535=CARTESIAN_POINT('',(3.59163519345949,9.06943392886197,-3.5));
#536=CARTESIAN_POINT('',(3.87827934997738,9.59964936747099,-3.5));
#537=CARTESIAN_POINT('',(4.02218351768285,9.86443365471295,-3.5));
#538=CARTESIAN_POINT('',(4.16652429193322,10.128978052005,-3.5));
#539=B_SPLINE_CURVE_WITH_KNOTS('',3,(#481,#482,#483,#484,#485,#486,#487,#488,#489,#490,#491,
#492,#493,#494,#495,#496,#497,#498,#499,#500,#501,#502,#503,#504,#505,#506,#507,#508,#509,#510,
#511,#512,#513,#514,#515,#516,#517,#518,#519,#520,#521,#522,#523,#524,#525,#526,#527,#528,#529,
#530,#531,#532,#533,#534,#535,#536,#537,#538),.UNSPECIFIED.,.F.,.F.,(4,2,2,2,2,2,2,2,2,2,2,2,2,
2,2,2,2,2,2,2,2,2,2,2,2,2,2,2,4),(0.,0.508991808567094,1.01806453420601,1.5299457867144,
2.04180256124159,2.56982945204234,3.09791584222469,3.62489659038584,4.1517095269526,
4.67563150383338,5.19950570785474,5.71657655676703,6.23365862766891,6.5996375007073,
6.96566721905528,7.6981430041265,8.07245060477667,8.44676062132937,8.82094246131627,
9.1951204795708,9.68730266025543,10.1795111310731,11.1640972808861,12.1496153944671,
13.1351679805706,14.041385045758,14.9476310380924,15.851760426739,16.7558429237),.UNSPECIFIED.);
#540=EDGE_CURVE('E366',#478,#60,#539,.T.);
#541=ORIENTED_EDGE('',*,*,#540,.T.);
#542=EDGE_CURVE('E367',#60,#427,#539,.T.);
#543=ORIENTED_EDGE('',*,*,#542,.T.);
#544=EDGE_LOOP('',(#470,#471,#472,#480,#541,#543));
#545=FACE_BOUND('',#544,.T.);
#546=ADVANCED_FACE('F159',(#545),#469,.T.);
#547=CARTESIAN_POINT('',(3.2,-4.04145188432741,0.));
#548=DIRECTION('',(0.,0.866025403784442,0.499999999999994));
#549=DIRECTION('',(0.,-0.499999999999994,0.866025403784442));
#550=AXIS2_PLACEMENT_3D('',#547,#548,#549);
#551=PLANE('',#550);
#552=ORIENTED_EDGE('',*,*,#331,.F.);
#553=DIRECTION('',(-1.,0.,0.));
#554=VECTOR('',#553,1.);
#555=CARTESIAN_POINT('',(3.2,-4.04145188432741,0.));
#556=LINE('',#555,#554);
#557=CARTESIAN_POINT('',(0.312607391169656,-4.04145188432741,0.));
#558=VERTEX_POINT('',#557);
#559=EDGE_CURVE('E337',#328,#558,#556,.T.);
#560=ORIENTED_EDGE('',*,*,#559,.T.);
#561=CARTESIAN_POINT('',(0.312674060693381,-2.0206104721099,-3.5002));
#562=CARTESIAN_POINT('',(0.261385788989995,-2.10941108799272,-3.34639282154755));
#563=CARTESIAN_POINT('',(0.214740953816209,-2.19897822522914,-3.19125798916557));
#564=CARTESIAN_POINT('',(0.133321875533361,-2.37966345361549,-2.87830199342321));
#565=CARTESIAN_POINT('',(0.0985764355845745,-2.47078475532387,-2.7204752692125));
#566=CARTESIAN_POINT('',(0.0444900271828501,-2.65189807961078,-2.40677778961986));
#567=CARTESIAN_POINT('',(0.024789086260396,-2.74186223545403,-2.2509553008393));
#568=CARTESIAN_POINT('',(0.00127013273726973,-2.9222138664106,-1.93857711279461));
#569=CARTESIAN_POINT('',(-0.00256735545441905,-3.01260068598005,-1.78202254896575));
#570=CARTESIAN_POINT('',(0.00541530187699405,-3.18149398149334,-1.48949078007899));
#571=CARTESIAN_POINT('',(0.0152754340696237,-3.26002573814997,-1.35346978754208));
#572=CARTESIAN_POINT('',(0.0465264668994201,-3.41657761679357,-1.08231397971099));
#573=CARTESIAN_POINT('',(0.0679280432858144,-3.49459719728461,-0.947180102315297));
#574=CARTESIAN_POINT('',(0.121430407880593,-3.65147186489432,-0.675465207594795));
#575=CARTESIAN_POINT('',(0.153757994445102,-3.73030709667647,-0.538918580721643));
#576=CARTESIAN_POINT('',(0.227128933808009,-3.88680174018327,-0.267861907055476));
#577=CARTESIAN_POINT('',(0.268155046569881,-3.96446315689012,-0.13334838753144));
#578=CARTESIAN_POINT('',(0.312674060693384,-4.04156735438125,0.000200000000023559));
#579=B_SPLINE_CURVE_WITH_KNOTS('',3,(#561,#562,#563,#564,#565,#566,#567,#568,#569,#570,#571,
#572,#573,#574,#575,#576,#577,#578),.UNSPECIFIED.,.F.,.F.,(4,2,2,2,2,2,2,2,4),(0.,
0.554793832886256,1.11092123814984,1.65328467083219,2.19498204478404,2.66665130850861,
3.13875761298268,3.6213361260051,4.10296698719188),.UNSPECIFIED.);
#580=EDGE_CURVE('E248',#64,#558,#579,.T.);
#581=ORIENTED_EDGE('',*,*,#580,.F.);
#582=EDGE_CURVE('E359',#478,#64,#579,.T.);
#583=ORIENTED_EDGE('',*,*,#582,.F.);
#584=ORIENTED_EDGE('',*,*,#479,.F.);
#585=ORIENTED_EDGE('',*,*,#300,.F.);
#586=EDGE_LOOP('',(#552,#560,#581,#583,#584,#585));
#587=FACE_BOUND('',#586,.T.);
#588=ADVANCED_FACE('F236',(#587),#551,.F.);
#589=CARTESIAN_POINT('',(3.2,-2.02072594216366,3.5));
#590=DIRECTION('',(0.,0.866025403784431,-0.500000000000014));
#591=DIRECTION('',(0.,0.500000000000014,0.866025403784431));
#592=AXIS2_PLACEMENT_3D('',#589,#590,#591);
#593=PLANE('',#592);
#594=ORIENTED_EDGE('',*,*,#400,.F.);
#595=DIRECTION('',(-1.,0.,0.));
#596=VECTOR('',#595,1.);
#597=CARTESIAN_POINT('',(3.2,-2.02072594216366,3.5));
#598=LINE('',#597,#596);
#599=CARTESIAN_POINT('',(0.312607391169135,-2.0207259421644,3.5));
#600=VERTEX_POINT('',#599);
#601=EDGE_CURVE('E339',#397,#600,#598,.T.);
#602=ORIENTED_EDGE('',*,*,#601,.T.);
#603=CARTESIAN_POINT('',(0.312674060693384,-4.04156735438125,-0.0001999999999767));
#604=CARTESIAN_POINT('',(0.261385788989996,-3.95276673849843,0.153607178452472));
#605=CARTESIAN_POINT('',(0.214740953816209,-3.863199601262,0.308742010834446));
#606=CARTESIAN_POINT('',(0.133321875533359,-3.68251437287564,0.621698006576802));
#607=CARTESIAN_POINT('',(0.0985764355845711,-3.59139307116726,0.779524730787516));
#608=CARTESIAN_POINT('',(0.0444900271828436,-3.41027974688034,1.09322221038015));
#609=CARTESIAN_POINT('',(0.0247890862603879,-3.32031559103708,1.24904469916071));
#610=CARTESIAN_POINT('',(0.00127013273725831,-3.13996396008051,1.56142288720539));
#611=CARTESIAN_POINT('',(-0.00256735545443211,-3.04957714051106,1.71797745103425));
#612=CARTESIAN_POINT('',(0.00541530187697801,-2.88068384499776,2.010509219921));
#613=CARTESIAN_POINT('',(0.0152754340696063,-2.80215208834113,2.14653021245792));
#614=CARTESIAN_POINT('',(0.0465264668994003,-2.64560020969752,2.417686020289));
#615=CARTESIAN_POINT('',(0.0679280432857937,-2.56758062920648,2.55281989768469));
#616=CARTESIAN_POINT('',(0.12143040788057,-2.41070596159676,2.82453479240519));
#617=CARTESIAN_POINT('',(0.153757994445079,-2.33187072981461,2.96108141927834));
#618=CARTESIAN_POINT('',(0.227128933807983,-2.1753760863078,3.2321380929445));
#619=CARTESIAN_POINT('',(0.268155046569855,-2.09771466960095,3.36665161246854));
#620=CARTESIAN_POINT('',(0.312674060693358,-2.02061047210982,3.5002));
#621=B_SPLINE_CURVE_WITH_KNOTS('',3,(#603,#604,#605,#606,#607,#608,#609,#610,#611,#612,#613,
#614,#615,#616,#617,#618,#619,#620),.UNSPECIFIED.,.F.,.F.,(4,2,2,2,2,2,2,2,4),(0.,
0.554793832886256,1.11092123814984,1.6532846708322,2.19498204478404,2.66665130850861,
3.13875761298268,3.6213361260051,4.10296698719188),.UNSPECIFIED.);
#622=EDGE_CURVE('E249',#41,#600,#621,.T.);
#623=ORIENTED_EDGE('',*,*,#622,.F.);
#624=EDGE_CURVE('E242',#558,#41,#621,.T.);
#625=ORIENTED_EDGE('',*,*,#624,.F.);
#626=ORIENTED_EDGE('',*,*,#559,.F.);
#627=ORIENTED_EDGE('',*,*,#329,.F.);
#628=EDGE_LOOP('',(#594,#602,#623,#625,#626,#627));
#629=FACE_BOUND('',#628,.T.);
#630=ADVANCED_FACE('F232',(#629),#593,.F.);
#631=CARTESIAN_POINT('',(3.2,2.02072594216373,3.5));
#632=DIRECTION('',(0.,0.,-1.));
#633=DIRECTION('',(-1.,0.,0.));
#634=AXIS2_PLACEMENT_3D('',#631,#632,#633);
#635=PLANE('',#634);
#636=ORIENTED_EDGE('',*,*,#410,.F.);
#637=DIRECTION('',(-1.,0.,0.));
#638=VECTOR('',#637,1.);
#639=CARTESIAN_POINT('',(3.2,2.02072594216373,3.5));
#640=LINE('',#639,#638);
#641=CARTESIAN_POINT('',(0.312607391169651,2.02072594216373,3.5));
#642=VERTEX_POINT('',#641);
#643=EDGE_CURVE('E341',#407,#642,#640,.T.);
#644=ORIENTED_EDGE('',*,*,#643,.T.);
#645=CARTESIAN_POINT('',(1.6975220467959,-5.40611730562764,3.5));
#646=CARTESIAN_POINT('',(1.62354446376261,-5.25343314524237,3.5));
#647=CARTESIAN_POINT('',(1.55028253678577,-5.10039613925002,3.5));
#648=CARTESIAN_POINT('',(1.40559293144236,-4.79342871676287,3.5));
#649=CARTESIAN_POINT('',(1.33416554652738,-4.6394981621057,3.5));
#650=CARTESIAN_POINT('',(1.19318392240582,-4.32975228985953,3.5));
#651=CARTESIAN_POINT('',(1.12364219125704,-4.17393125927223,3.5));
#652=CARTESIAN_POINT('',(0.987433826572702,-3.8610422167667,3.5));
#653=CARTESIAN_POINT('',(0.920767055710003,-3.703974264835,3.5));
#654=CARTESIAN_POINT('',(0.789017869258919,-3.38335155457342,3.5));
#655=CARTESIAN_POINT('',(0.724052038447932,-3.2197486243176,3.5));
#656=CARTESIAN_POINT('',(0.599090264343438,-2.89062062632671,3.5));
#657=CARTESIAN_POINT('',(0.539094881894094,-2.72509534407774,3.5));
#658=CARTESIAN_POINT('',(0.425665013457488,-2.39217631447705,3.5));
#659=CARTESIAN_POINT('',(0.372217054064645,-2.22478720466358,3.5));
#660=CARTESIAN_POINT('',(0.273611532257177,-1.88760803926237,3.5));
#661=CARTESIAN_POINT('',(0.228451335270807,-1.71781876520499,3.5));
#662=CARTESIAN_POINT('',(0.148842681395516,-1.37668395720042,3.5));
#663=CARTESIAN_POINT('',(0.114336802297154,-1.2053520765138,3.5));
#664=CARTESIAN_POINT('',(0.0580012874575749,-0.860580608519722,3.5));
#665=CARTESIAN_POINT('',(0.0361704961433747,-0.687141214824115,3.5));
#666=CARTESIAN_POINT('',(0.00721291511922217,-0.341277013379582,3.5));
#667=CARTESIAN_POINT('',(-0.00010114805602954,-0.16886828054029,3.5));
#668=CARTESIAN_POINT('',(0.0001032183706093,0.175953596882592,3.5));
#669=CARTESIAN_POINT('',(0.00762196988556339,0.348366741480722,3.5));
#670=CARTESIAN_POINT('',(0.0325058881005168,0.641728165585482,3.5));
#671=CARTESIAN_POINT('',(0.0463516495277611,0.762992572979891,3.5));
#672=CARTESIAN_POINT('',(0.0805067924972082,1.00461398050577,3.5));
#673=CARTESIAN_POINT('',(0.100817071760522,1.12497085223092,3.5));
#674=CARTESIAN_POINT('',(0.170375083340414,1.48453137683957,3.5));
#675=CARTESIAN_POINT('',(0.228236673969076,1.72208616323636,3.5));
#676=CARTESIAN_POINT('',(0.328316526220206,2.07725702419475,3.5));
#677=CARTESIAN_POINT('',(0.36434915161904,2.19672070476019,3.5));
#678=CARTESIAN_POINT('',(0.440093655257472,2.43448713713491,3.5));
#679=CARTESIAN_POINT('',(0.479805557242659,2.5527898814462,3.5));
#680=CARTESIAN_POINT('',(0.562276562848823,2.78827311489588,3.5));
#681=CARTESIAN_POINT('',(0.605034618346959,2.90545397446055,3.5));
#682=CARTESIAN_POINT('',(0.693101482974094,3.13884909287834,3.5));
#683=CARTESIAN_POINT('',(0.738410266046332,3.2550633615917,3.5));
#684=CARTESIAN_POINT('',(0.845779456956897,3.52315412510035,3.5));
#685=CARTESIAN_POINT('',(0.908616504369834,3.67471898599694,3.5));
#686=CARTESIAN_POINT('',(1.03721699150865,3.97660499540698,3.5));
#687=CARTESIAN_POINT('',(1.1029805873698,4.12692607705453,3.5));
#688=CARTESIAN_POINT('',(1.30378004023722,4.57638177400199,3.5));
#689=CARTESIAN_POINT('',(1.44230315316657,4.8739566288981,3.5));
#690=CARTESIAN_POINT('',(1.72558516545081,5.46643785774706,3.5));
#691=CARTESIAN_POINT('',(1.87034984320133,5.76134143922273,3.5));
#692=CARTESIAN_POINT('',(2.1641152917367,6.34903869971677,3.5));
#693=CARTESIAN_POINT('',(2.31311621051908,6.64183230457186,3.5));
#694=CARTESIAN_POINT('',(2.60201869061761,7.20235284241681,3.5));
#695=CARTESIAN_POINT('',(2.74168720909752,7.47020029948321,3.5));
#696=CARTESIAN_POINT('',(3.0229544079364,8.00488966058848,3.5));
#697=CARTESIAN_POINT('',(3.1645531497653,8.27173153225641,3.5));
#698=CARTESIAN_POINT('',(3.44889526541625,8.80400274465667,3.5));
#699=CARTESIAN_POINT('',(3.59163519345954,9.06943392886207,3.5));
#700=CARTESIAN_POINT('',(3.87827934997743,9.59964936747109,3.5));
#701=CARTESIAN_POINT('',(4.0221835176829,9.86443365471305,3.5));
#702=CARTESIAN_POINT('',(4.16652429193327,10.1289780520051,3.5));
#703=B_SPLINE_CURVE_WITH_KNOTS('',3,(#645,#646,#647,#648,#649,#650,#651,#652,#653,#654,#655,
#656,#657,#658,#659,#660,#661,#662,#663,#664,#665,#666,#667,#668,#669,#670,#671,#672,#673,#674,
#675,#676,#677,#678,#679,#680,#681,#682,#683,#684,#685,#686,#687,#688,#689,#690,#691,#692,#693,
#694,#695,#696,#697,#698,#699,#700,#701,#702),.UNSPECIFIED.,.F.,.F.,(4,2,2,2,2,2,2,2,2,2,2,2,2,
2,2,2,2,2,2,2,2,2,2,2,2,2,2,2,4),(0.,0.50899180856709,1.018064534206,1.52994578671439,
2.04180256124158,2.56982945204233,3.09791584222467,3.62489659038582,4.15170952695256,
4.67563150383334,5.1995057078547,5.71657655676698,6.23365862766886,6.59963750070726,
6.96566721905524,7.69814300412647,8.07245060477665,8.44676062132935,8.82094246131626,
9.1951204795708,9.68730266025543,10.1795111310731,11.1640972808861,12.1496153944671,
13.1351679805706,14.041385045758,14.9476310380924,15.851760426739,16.7558429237),.UNSPECIFIED.);
#704=EDGE_CURVE('E247',#43,#642,#703,.T.);
#705=ORIENTED_EDGE('',*,*,#704,.F.);
#706=EDGE_CURVE('E258',#600,#43,#703,.T.);
#707=ORIENTED_EDGE('',*,*,#706,.F.);
#708=ORIENTED_EDGE('',*,*,#601,.F.);
#709=ORIENTED_EDGE('',*,*,#398,.F.);
#710=EDGE_LOOP('',(#636,#644,#705,#707,#708,#709));
#711=FACE_BOUND('',#710,.T.);
#712=ADVANCED_FACE('F235',(#711),#635,.F.);
#713=CARTESIAN_POINT('',(3.2,4.04145188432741,0.));
#714=DIRECTION('',(0.,-0.866025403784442,-0.499999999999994));
#715=DIRECTION('',(0.,0.499999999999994,-0.866025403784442));
#716=AXIS2_PLACEMENT_3D('',#713,#714,#715);
#717=PLANE('',#716);
#718=ORIENTED_EDGE('',*,*,#183,.F.);
#719=ORIENTED_EDGE('',*,*,#459,.T.);
#720=CARTESIAN_POINT('',(0.31267406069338,2.0206104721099,3.5002));
#721=CARTESIAN_POINT('',(0.261385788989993,2.10941108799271,3.34639282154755));
#722=CARTESIAN_POINT('',(0.214740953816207,2.19897822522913,3.19125798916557));
#723=CARTESIAN_POINT('',(0.13332187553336,2.37966345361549,2.87830199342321));
#724=CARTESIAN_POINT('',(0.0985764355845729,2.47078475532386,2.7204752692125));
#725=CARTESIAN_POINT('',(0.0444900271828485,2.65189807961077,2.40677778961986));
#726=CARTESIAN_POINT('',(0.0247890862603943,2.74186223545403,2.2509553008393));
#727=CARTESIAN_POINT('',(0.00127013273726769,2.92221386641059,1.93857711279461));
#728=CARTESIAN_POINT('',(-0.00256735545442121,3.01260068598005,1.78202254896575));
#729=CARTESIAN_POINT('',(0.00541530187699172,3.18149398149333,1.48949078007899));
#730=CARTESIAN_POINT('',(0.0152754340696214,3.26002573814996,1.35346978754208));
#731=CARTESIAN_POINT('',(0.0465264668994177,3.41657761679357,1.08231397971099));
#732=CARTESIAN_POINT('',(0.0679280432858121,3.49459719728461,0.947180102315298));
#733=CARTESIAN_POINT('',(0.12143040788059,3.65147186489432,0.675465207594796));
#734=CARTESIAN_POINT('',(0.1537579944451,3.73030709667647,0.538918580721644));
#735=CARTESIAN_POINT('',(0.227128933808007,3.88680174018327,0.267861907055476));
#736=CARTESIAN_POINT('',(0.268155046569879,3.96446315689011,0.13334838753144));
#737=CARTESIAN_POINT('',(0.312674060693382,4.04156735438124,-0.000200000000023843));
#738=B_SPLINE_CURVE_WITH_KNOTS('',3,(#720,#721,#722,#723,#724,#725,#726,#727,#728,#729,#730,
#731,#732,#733,#734,#735,#736,#737),.UNSPECIFIED.,.F.,.F.,(4,2,2,2,2,2,2,2,4),(0.,
0.554793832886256,1.11092123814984,1.65328467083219,2.19498204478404,2.66665130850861,
3.13875761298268,3.62133612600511,4.10296698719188),.UNSPECIFIED.);
#739=EDGE_CURVE('E250',#52,#452,#738,.T.);
#740=ORIENTED_EDGE('',*,*,#739,.F.);
#741=EDGE_CURVE('E362',#642,#52,#738,.T.);
#742=ORIENTED_EDGE('',*,*,#741,.F.);
#743=ORIENTED_EDGE('',*,*,#643,.F.);
#744=ORIENTED_EDGE('',*,*,#408,.F.);
#745=EDGE_LOOP('',(#718,#719,#740,#742,#743,#744));
#746=FACE_BOUND('',#745,.T.);
#747=ADVANCED_FACE('F390',(#746),#717,.F.);
#748=CARTESIAN_POINT('',(0.,0.,0.));
#749=DIRECTION('',(1.,0.,0.));
#750=DIRECTION('',(0.,0.,-1.));
#751=AXIS2_PLACEMENT_3D('',#748,#749,#750);
#752=CONICAL_SURFACE('',#751,3.5,1.0471975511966);
#753=ORIENTED_EDGE('',*,*,#622,.T.);
#754=ORIENTED_EDGE('',*,*,#706,.T.);
#755=ORIENTED_EDGE('',*,*,#44,.F.);
#756=EDGE_LOOP('',(#753,#754,#755));
#757=FACE_BOUND('',#756,.T.);
#758=ADVANCED_FACE('F396',(#757),#752,.T.);
#759=ORIENTED_EDGE('',*,*,#624,.T.);
#760=ORIENTED_EDGE('',*,*,#67,.F.);
#761=ORIENTED_EDGE('',*,*,#580,.T.);
#762=EDGE_LOOP('',(#759,#760,#761));
#763=FACE_BOUND('',#762,.T.);
#764=ADVANCED_FACE('F402',(#763),#752,.T.);
#765=ORIENTED_EDGE('',*,*,#582,.T.);
#766=ORIENTED_EDGE('',*,*,#65,.F.);
#767=ORIENTED_EDGE('',*,*,#540,.F.);
#768=EDGE_LOOP('',(#765,#766,#767));
#769=FACE_BOUND('',#768,.T.);
#770=ADVANCED_FACE('F409',(#769),#752,.T.);
#771=ORIENTED_EDGE('',*,*,#61,.F.);
#772=ORIENTED_EDGE('',*,*,#449,.T.);
#773=ORIENTED_EDGE('',*,*,#542,.F.);
#774=EDGE_LOOP('',(#771,#772,#773));
#775=FACE_BOUND('',#774,.T.);
#776=ADVANCED_FACE('F194',(#775),#752,.T.);
#777=ORIENTED_EDGE('',*,*,#739,.T.);
#778=ORIENTED_EDGE('',*,*,#453,.T.);
#779=ORIENTED_EDGE('',*,*,#57,.F.);
#780=EDGE_LOOP('',(#777,#778,#779));
#781=FACE_BOUND('',#780,.T.);
#782=ADVANCED_FACE('F410',(#781),#752,.T.);
#783=ORIENTED_EDGE('',*,*,#704,.T.);
#784=ORIENTED_EDGE('',*,*,#741,.T.);
#785=ORIENTED_EDGE('',*,*,#53,.F.);
#786=EDGE_LOOP('',(#783,#784,#785));
#787=FACE_BOUND('',#786,.T.);
#788=ADVANCED_FACE('F403',(#787),#752,.T.);
#789=CARTESIAN_POINT('',(0.,0.,0.));
#790=DIRECTION('',(1.,0.,0.));
#791=DIRECTION('',(0.,0.,-1.));
#792=AXIS2_PLACEMENT_3D('',#789,#790,#791);
#793=CYLINDRICAL_SURFACE('',#792,2.);
#794=ORIENTED_EDGE('',*,*,#31,.T.);
#795=EDGE_LOOP('',(#794));
#796=FACE_BOUND('',#795,.T.);
#797=CARTESIAN_POINT('',(0.0253999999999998,0.,0.));
#798=DIRECTION('',(1.,0.,0.));
#799=DIRECTION('',(0.,0.,-1.));
#800=AXIS2_PLACEMENT_3D('',#797,#798,#799);
#801=CIRCLE('',#800,2.);
#802=CARTESIAN_POINT('',(0.0253999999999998,0.,-2.));
#803=VERTEX_POINT('',#802);
#804=EDGE_CURVE('E302',#803,#803,#801,.T.);
#805=ORIENTED_EDGE('',*,*,#804,.T.);
#806=EDGE_LOOP('',(#805));
#807=FACE_BOUND('',#806,.T.);
#808=ADVANCED_FACE('F136',(#796,#807),#793,.F.);
#809=CARTESIAN_POINT('',(0.294979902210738,0.,0.));
#810=DIRECTION('',(-1.,0.,0.));
#811=DIRECTION('',(0.,0.,1.));
#812=AXIS2_PLACEMENT_3D('',#809,#810,#811);
#813=CONICAL_SURFACE('',#812,1.615,0.959931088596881);
#814=CARTESIAN_POINT('',(0.270472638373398,0.,0.));
#815=DIRECTION('',(-1.,0.,0.));
#816=DIRECTION('',(0.,0.,1.));
#817=AXIS2_PLACEMENT_3D('',#814,#815,#816);
#818=CIRCLE('',#817,1.65);
#819=CARTESIAN_POINT('',(0.270472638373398,0.,1.65));
#820=VERTEX_POINT('',#819);
#821=EDGE_CURVE('E185',#820,#820,#818,.F.);
#822=ORIENTED_EDGE('',*,*,#821,.T.);
#823=EDGE_LOOP('',(#822));
#824=FACE_BOUND('',#823,.T.);
#825=ORIENTED_EDGE('',*,*,#804,.F.);
#826=EDGE_LOOP('',(#825));
#827=FACE_BOUND('',#826,.T.);
#828=ADVANCED_FACE('F127',(#824,#827),#813,.F.);
#829=CARTESIAN_POINT('',(5.79142002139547,0.,0.));
#830=DIRECTION('',(-1.,0.,0.));
#831=DIRECTION('',(0.,0.,1.));
#832=AXIS2_PLACEMENT_3D('',#829,#830,#831);
#833=CONICAL_SURFACE('',#832,0.,1.02974425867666);
#834=CARTESIAN_POINT('',(4.8,0.,0.));
#835=DIRECTION('',(-1.,0.,0.));
#836=DIRECTION('',(0.,0.,1.));
#837=AXIS2_PLACEMENT_3D('',#834,#835,#836);
#838=CIRCLE('',#837,1.65);
#839=CARTESIAN_POINT('',(4.8,0.,1.65));
#840=VERTEX_POINT('',#839);
#841=EDGE_CURVE('E299',#840,#840,#838,.T.);
#842=ORIENTED_EDGE('',*,*,#841,.T.);
#843=EDGE_LOOP('',(#842));
#844=FACE_BOUND('',#843,.T.);
#845=CARTESIAN_POINT('',(5.79142002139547,0.,0.));
#846=VERTEX_POINT('',#845);
#847=VERTEX_LOOP('',#846);
#848=FACE_BOUND('',#847,.T.);
#849=ADVANCED_FACE('F124',(#844,#848),#833,.F.);
#850=CARTESIAN_POINT('',(0.,0.,0.));
#851=DIRECTION('',(-1.,0.,0.));
#852=DIRECTION('',(0.,0.,1.));
#853=AXIS2_PLACEMENT_3D('',#850,#851,#852);
#854=CYLINDRICAL_SURFACE('',#853,1.65);
#855=ORIENTED_EDGE('',*,*,#821,.F.);
#856=EDGE_LOOP('',(#855));
#857=FACE_BOUND('',#856,.T.);
#858=ORIENTED_EDGE('',*,*,#841,.F.);
#859=EDGE_LOOP('',(#858));
#860=FACE_BOUND('',#859,.T.);
#861=ADVANCED_FACE('F126',(#857,#860),#854,.F.);
#862=CARTESIAN_POINT('',(3.32,0.,0.));
#863=DIRECTION('',(-1.,0.,0.));
#864=DIRECTION('',(0.,0.,1.));
#865=AXIS2_PLACEMENT_3D('',#862,#863,#864);
#866=TOROIDAL_SURFACE('',#865,3.37,0.12);
#867=ORIENTED_EDGE('',*,*,#84,.F.);
#868=EDGE_LOOP('',(#867));
#869=FACE_BOUND('',#868,.T.);
#870=ORIENTED_EDGE('',*,*,#132,.F.);
#871=EDGE_LOOP('',(#870));
#872=FACE_BOUND('',#871,.T.);
#873=ADVANCED_FACE('F34',(#869,#872),#866,.F.);
#874=CLOSED_SHELL('',(#71,#119,#147,#156,#209,#278,#307,#336,#405,#415,#464,#546,#588,#630,#712,
#747,#758,#764,#770,#776,#782,#788,#808,#828,#849,#861,#873));
#875=MANIFOLD_SOLID_BREP('B2',#874);
#876=ADVANCED_BREP_SHAPE_REPRESENTATION('',(#18,#875),#14);
#877=SHAPE_DEFINITION_REPRESENTATION(#9,#876);
ENDSEC;
END-ISO-10303-21;
